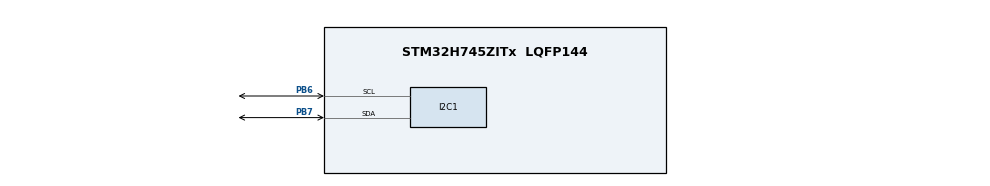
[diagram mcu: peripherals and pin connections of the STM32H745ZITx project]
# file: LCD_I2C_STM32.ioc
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CortexM4.IPs=BDMA,CORTEX_M4\:I,DEBUG,DMA,FATFS_M4\:I,FREERTOS_M4\:I,GPIO,IWDG2\:I,MDMA,NVIC2\:I,OPENAMP_M4\:I,PDM2PCM_M4\:I,PWR,RCC,RESMGR_UTILITY,SYS_M4\:I,USB_DEVICE_M4\:I,USB_HOST_M4\:I,VREFBUF,WWDG2\:I
CortexM7.IPs=BDMA\:I,CORTEX_M7\:I,DEBUG\:I,DMA\:I,FATFS_M7\:I,FREERTOS_M7\:I,GPIO\:I,IWDG1\:I,MDMA\:I,NVIC1\:I,OPENAMP_M7\:I,PDM2PCM_M7\:I,PWR\:I,RCC\:I,RESMGR_UTILITY\:I,SYS\:I,USB_DEVICE_M7\:I,USB_HOST_M7\:I,VREFBUF\:I,WWDG1\:I,I2C1\:I
I2C1.Timing=0x00808CD2
Mcu.Family=STM32H7
Mcu.Name=STM32H745ZITx
Mcu.Package=LQFP144
NVIC1.PriorityGroup=NVIC_PRIORITYGROUP_4
NVIC2.PriorityGroup=NVIC_PRIORITYGROUP_4
PB6.GPIO_Pu=GPIO_PULLUP
PB6.GPIO_Speed=GPIO_SPEED_FREQ_VERY_HIGH
PB6.Mode=I2C
PB6.PinAttribute=CortexM7
PB6.Signal=I2C1_SCL
PB7.GPIO_Pu=GPIO_PULLUP
PB7.GPIO_Speed=GPIO_SPEED_FREQ_VERY_HIGH
PB7.Mode=I2C
PB7.PinAttribute=CortexM7
PB7.Signal=I2C1_SDA
ProjectManager.HeapSize=M4-0x200,M7-0x200
ProjectManager.StackSize=M4-0x400,M7-0x400
ProjectManager.TargetToolchain=STM32CubeIDE
RCC.ADCFreq_Value=129000000
RCC.APB1Freq_Value=36000000
RCC.APB2Freq_Value=72000000
RCC.APB3Freq_Value=72000000
RCC.APB4Freq_Value=72000000
RCC.CortexFreq_Value=72000000
RCC.D1CPRE=RCC_SYSCLK_DIV2
RCC.D2PPRE1=RCC_APB1_DIV2
RCC.DIVM1=4
RCC.DIVN1=18
RCC.HCLKFreq_Value=72000000
RCC.PLLFRACN=0
RCC.SYSCLKFreq_VALUE=144000000
RCC.SYSCLKSource=RCC_SYSCLKSOURCE_PLLCLK
RCC.USBFreq_Value=144000000
SYS.userName=SYS_M7
board=custom

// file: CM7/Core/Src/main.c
/* USER CODE BEGIN Header */
/**
  ******************************************************************************
  * @file           : main.c
  * @brief          : Main program body
  ******************************************************************************
  * @attention
  *
  * Copyright (c) 2023 STMicroelectronics.
  * All rights reserved.
  *
  * This software is licensed under terms that can be found in the LICENSE file
  * in the root directory of this software component.
  * If no LICENSE file comes with this software, it is provided AS-IS.
  *
  ******************************************************************************
  */
/* USER CODE END Header */
#include "main.h"

/* USER CODE BEGIN PD */

#ifndef HSEM_ID_0
#define HSEM_ID_0 (0U) /* HW semaphore 0*/
#endif
/* USER CODE END PD */

I2C_HandleTypeDef hi2c1;

void SystemClock_Config(void);
static void MX_GPIO_Init(void);
static void MX_I2C1_Init(void);

int main(void)
{
/* USER CODE BEGIN Boot_Mode_Sequence_0 */
  int32_t timeout;
/* USER CODE END Boot_Mode_Sequence_0 */

/* USER CODE BEGIN Boot_Mode_Sequence_1 */
  /* Wait until CPU2 boots and enters in stop mode or timeout*/
  timeout = 0xFFFF;
  while((__HAL_RCC_GET_FLAG(RCC_FLAG_D2CKRDY) != RESET) && (timeout-- > 0));
  if ( timeout < 0 )
  {
  Error_Handler();
  }
/* USER CODE END Boot_Mode_Sequence_1 */
  /* MCU Configuration--------------------------------------------------------*/

  /* Reset of all peripherals, Initializes the Flash interface and the Systick. */
  HAL_Init();

  /* Configure the system clock */
  SystemClock_Config();
/* USER CODE BEGIN Boot_Mode_Sequence_2 */
/* When system initialization is finished, Cortex-M7 will release Cortex-M4 by means of
HSEM notification */
/*HW semaphore Clock enable*/
__HAL_RCC_HSEM_CLK_ENABLE();
/*Take HSEM */
HAL_HSEM_FastTake(HSEM_ID_0);
/*Release HSEM in order to notify the CPU2(CM4)*/
HAL_HSEM_Release(HSEM_ID_0,0);
/* wait until CPU2 wakes up from stop mode */
timeout = 0xFFFF;
while((__HAL_RCC_GET_FLAG(RCC_FLAG_D2CKRDY) == RESET) && (timeout-- > 0));
if ( timeout < 0 )
{
Error_Handler();
}
/* USER CODE END Boot_Mode_Sequence_2 */

  /* Initialize all configured peripherals */
  MX_GPIO_Init();
  MX_I2C1_Init();

  /* Infinite loop */
  while (1)
  {

  }
}

void SystemClock_Config(void)
{
  RCC_OscInitTypeDef RCC_OscInitStruct = {0};
  RCC_ClkInitTypeDef RCC_ClkInitStruct = {0};

  /** Supply configuration update enable
  */
  HAL_PWREx_ConfigSupply(PWR_DIRECT_SMPS_SUPPLY);

  /** Configure the main internal regulator output voltage
  */
  __HAL_PWR_VOLTAGESCALING_CONFIG(PWR_REGULATOR_VOLTAGE_SCALE3);

  while(!__HAL_PWR_GET_FLAG(PWR_FLAG_VOSRDY)) {}

  /** Initializes the RCC Oscillators according to the specified parameters
  * in the RCC_OscInitTypeDef structure.
  */
  RCC_OscInitStruct.OscillatorType = RCC_OSCILLATORTYPE_HSI;
  RCC_OscInitStruct.HSIState = RCC_HSI_DIV1;
  RCC_OscInitStruct.HSICalibrationValue = RCC_HSICALIBRATION_DEFAULT;
  RCC_OscInitStruct.PLL.PLLState = RCC_PLL_NONE;
  if (HAL_RCC_OscConfig(&RCC_OscInitStruct) != HAL_OK)
  {
    Error_Handler();
  }

  /** Initializes the CPU, AHB and APB buses clocks
  */
  RCC_ClkInitStruct.ClockType = RCC_CLOCKTYPE_HCLK|RCC_CLOCKTYPE_SYSCLK
                              |RCC_CLOCKTYPE_PCLK1|RCC_CLOCKTYPE_PCLK2
                              |RCC_CLOCKTYPE_D3PCLK1|RCC_CLOCKTYPE_D1PCLK1;
  RCC_ClkInitStruct.SYSCLKSource = RCC_SYSCLKSOURCE_HSI;
  RCC_ClkInitStruct.SYSCLKDivider = RCC_SYSCLK_DIV1;
  RCC_ClkInitStruct.AHBCLKDivider = RCC_HCLK_DIV1;
  RCC_ClkInitStruct.APB3CLKDivider = RCC_APB3_DIV1;
  RCC_ClkInitStruct.APB1CLKDivider = RCC_APB1_DIV2;
  RCC_ClkInitStruct.APB2CLKDivider = RCC_APB2_DIV1;
  RCC_ClkInitStruct.APB4CLKDivider = RCC_APB4_DIV1;

  if (HAL_RCC_ClockConfig(&RCC_ClkInitStruct, FLASH_LATENCY_1) != HAL_OK)
  {
    Error_Handler();
  }
}

static void MX_I2C1_Init(void)
{

  hi2c1.Instance = I2C1;
  hi2c1.Init.Timing = 0x00707CBB;
  hi2c1.Init.OwnAddress1 = 0;
  hi2c1.Init.AddressingMode = I2C_ADDRESSINGMODE_7BIT;
  hi2c1.Init.DualAddressMode = I2C_DUALADDRESS_DISABLE;
  hi2c1.Init.OwnAddress2 = 0;
  hi2c1.Init.OwnAddress2Masks = I2C_OA2_NOMASK;
  hi2c1.Init.GeneralCallMode = I2C_GENERALCALL_DISABLE;
  hi2c1.Init.NoStretchMode = I2C_NOSTRETCH_DISABLE;
  if (HAL_I2C_Init(&hi2c1) != HAL_OK)
  {
    Error_Handler();
  }

  /** Configure Analogue filter
  */
  if (HAL_I2CEx_ConfigAnalogFilter(&hi2c1, I2C_ANALOGFILTER_ENABLE) != HAL_OK)
  {
    Error_Handler();
  }

  /** Configure Digital filter
  */
  if (HAL_I2CEx_ConfigDigitalFilter(&hi2c1, 0) != HAL_OK)
  {
    Error_Handler();
  }

}

static void MX_GPIO_Init(void)
{

  /* GPIO Ports Clock Enable */
  __HAL_RCC_GPIOB_CLK_ENABLE();

}

void Error_Handler(void)
{
  __disable_irq();
  while (1)
  {
  }
}
